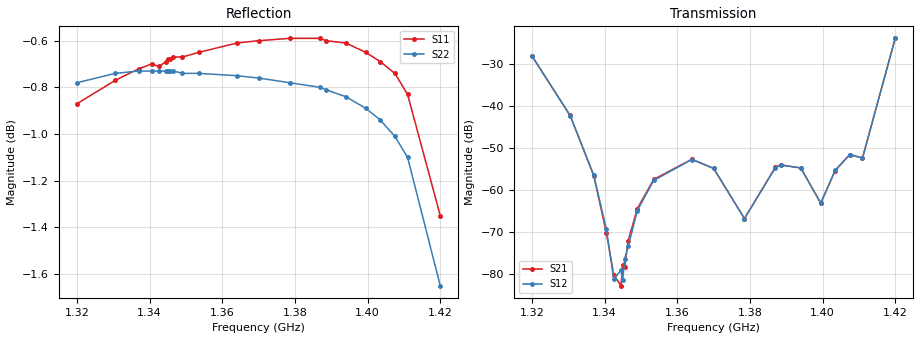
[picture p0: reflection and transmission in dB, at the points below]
!Agilent Technologies,E8363B,SG43030131,A.07.50.48
!Agilent E8363B: A.07.50.48
!Date: Friday, November 21, 2025 21:35:45
!Correction: S11(Full 2 Port(1,2))
!S21(Full 2 Port(1,2))
!S12(Full 2 Port(1,2))
!S22(Full 2 Port(1,2))
!S2P File: Measurements: S11, S21, S12, S22:
# Hz S  dB  R 50
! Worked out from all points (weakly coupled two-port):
!   201 points, 1.32 GHz to 1.42 GHz, reference 50 ohm
!   highest |S21| = -23.83 dB at 1.42 GHz (marker M1); lowest = -82.8 dB at 1.345 GHz (marker M2)
!   lowest |S11| = -1.3 dB at 1.42 GHz (marker M3), VSWR 12.93, Z = 57.2 - j177 ohm
!   |S11| at or under -10 dB: nowhere
!   |S22| runs from -1.6 to -0.7 dB; largest |S21 - S12| = 0.0001
!   S11 on the Smith chart (normalised r, x): 1.32 GHz: 0.05, +0.03; 1.341 GHz: 0.05, +0.42; 1.364 GHz: 0.07, +0.92; 1.389 GHz: 0.17, +1.99; 1.407 GHz: 2.88, +7.63; 1.42 GHz: 1.14, -3.55
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1.32e9  -0.87 176.4  -28.06 -53.4  -28.06 -53.4  -0.78 -128.7
1.3305e9  -0.77 153.5  -42.20 -69.0  -42.23 -68.9  -0.74 -150.5
1.337e9  -0.72 140.8  -56.54 -67.1  -56.47 -66.1  -0.73 -163.4
1.3405e9  -0.70 134.4  -70.28 -43.1  -69.37 -36.9  -0.73 -170.3
1.3425e9  -0.71 130.8  -80.19 23.5  -81.17 10.9  -0.73 -174.1
1.3445e9  -0.69 127.2  -82.76 129.1  -79.10 129.5  -0.73 -178.0
1.345e9  -0.68 126.3  -77.87 146.7  -81.44 144.5  -0.73 -178.9
1.3455e9  -0.68 125.5  -78.29 174.4  -76.43 176.3  -0.73 -179.9
1.3465e9  -0.67 123.7  -72.02 -174.8  -73.34 -172.4  -0.73 178.1
1.349e9  -0.67 119.4  -64.37 -153.5  -64.85 -149.5  -0.74 173.3
1.3535e9  -0.65 111.7  -57.44 -143.6  -57.68 -143.6  -0.74 164.6
1.364e9  -0.61 94.3  -52.64 -149.8  -52.70 -149.7  -0.75 143.9
1.37e9  -0.60 84.6  -54.82 -153.1  -54.79 -152.8  -0.76 131.8
1.3785e9  -0.59 70.5  -66.76 -86.2  -66.77 -83.6  -0.78 113.7
1.387e9  -0.59 55.9  -54.53 -22.0  -54.68 -21.9  -0.80 94.4
1.3885e9  -0.60 53.1  -53.97 -22.4  -54.03 -22.4  -0.81 90.8
1.394e9  -0.61 42.8  -54.70 -22.0  -54.72 -21.5  -0.84 76.9
1.3995e9  -0.65 31.7  -63.03 30.4  -63.11 31.1  -0.89 61.8
1.4035e9  -0.69 22.8  -55.34 102.2  -55.22 102.0  -0.94 49.7
1.4075e9  -0.74 13.1  -51.51 116.1  -51.51 115.9  -1.01 36.4
1.411e9  -0.83 3.6  -52.33 170.9  -52.38 170.9  -1.10 23.5
1.42e9  -1.35 -28.8  -23.83 -143.1  -23.83 -143.1  -1.65 -19.2
